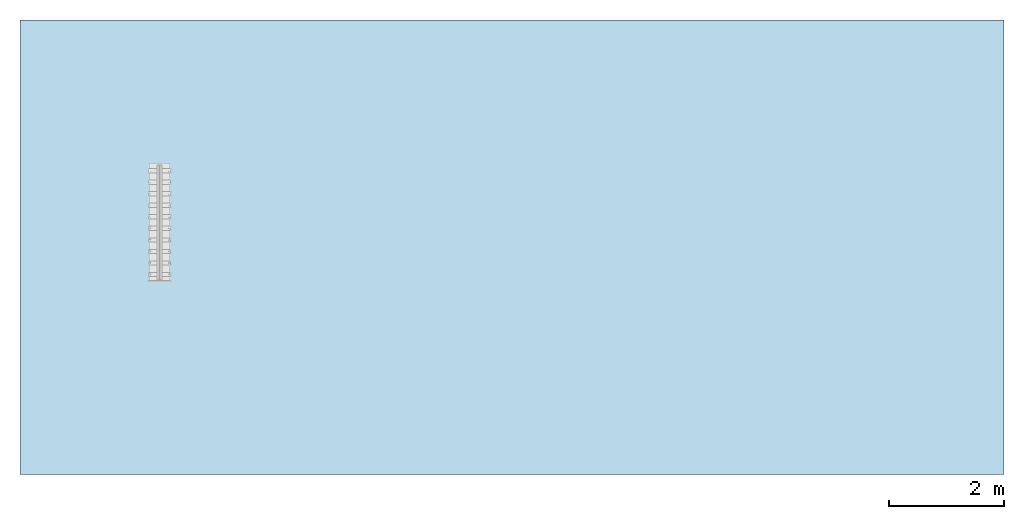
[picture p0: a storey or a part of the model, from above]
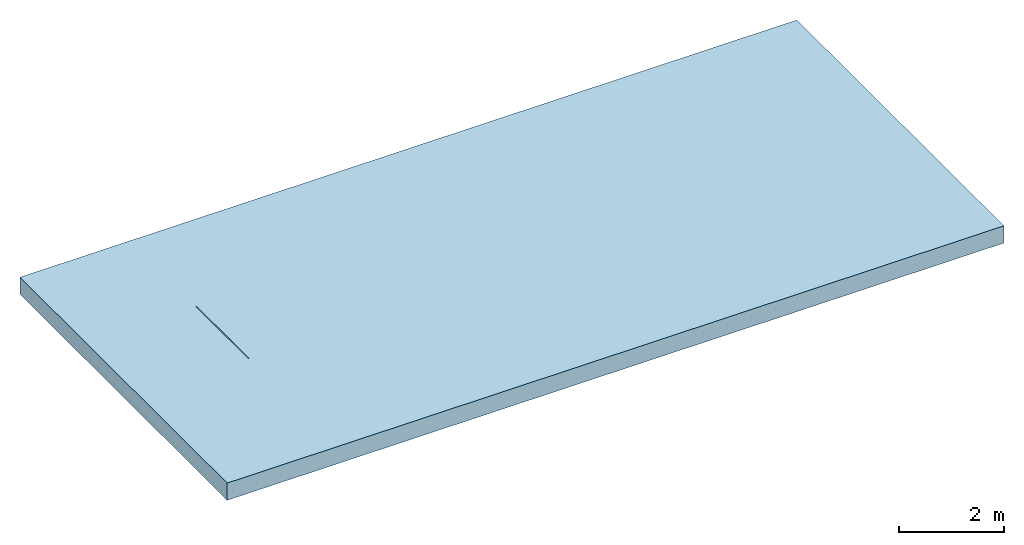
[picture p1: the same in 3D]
Properties of the parts of a building model (IFC2X3)

# File
Description: ViewDefinition [CoordinationView]
File name: 32814 - Q-Slot Edge - G.S.ifc
Time: 2013-07-12T11:23:24
Written by: Autodesk Revit 2013
Made in: 20120221_2030(x64)

# IfcProject, Project Number
LongName: Project Name; Phase: Project Status

# IfcSite, Default
RefLatitude: 42, 21, 30, 344238; RefLongitude: -71, -3, -35, -194702; RefElevation: 0 mm

# IfcBuilding
Pset_BuildingCommon - NumberOfStoreys: 1
Other - Project Address: ## Street City, State Zip; Project Name: Project Name; Client Name: Owner; Project Number: Project Number; Project Status: Project Status; Project Issue Date: Issue Date

# IfcBuildingStorey, Level 1
LongName: Level 1; Elevation: 0 mm
Constraints - Elevation Base: 0; Elevation: 0 mm
Graphics - Line Pattern: Center; Symbol at End 2 Default: yes; Symbol: M_Level Head - Circle: M_Level Head - Circle; Line Weight: 1; Symbol at End 1 Default: no; Color: 0
Identity Data - Structural: no; Building Story: yes; Name: Level 1
Dimensions - Computation Height: 0 mm

# IfcFlowTerminal: 32814 - Q-Slot Edge - G.S, Qmax 350:32814 - Q-Slot Edge - G.S:32814 - Q-Slot Edge - G.S:562865
In: Level 1
Identity Data - Mark: 40; OmniClass Number: 23.70.50.24; URL: www.aco.co.uk; OmniClass Title: Rainwater Removal; Product Page URL: http://www.aco.co.uk/product_detail.php?id=79; Address: ACO Business Park, Hitchin Road, Shefford, Bedfordshire, United Kingdom SG17 5TE; Maintenance Guidelines: http://www.aco.co.uk/download.php?id=220; e-mail Technical: technical@aco.co.uk; Fax: +44 (0)1462 815895; Assembly Code: D2040; Product Brochure: http://www.aco.co.uk/download.php?id=220; Product Code: 32814; Installation Guidelines: http://www.aco.co.uk/download.php?id=220; Telephone: +44 (0)1462 816666; Price: POA - contact ACO; Type Comments: ACO Qmax 350 channel assembly complete with ACO Q-Slot galvanised steel edge rail; Manufacturer: ACO Technologies plc - ACO Water Management Division; Model Description: High capacity slot drainage channel system; Model: ACO Qmax 350; Cost: 0; e-mail Sales: customersupport@aco.co.uk; Assembly Description: Rain Water Drainage
Constraints - Moves With Nearby Elements: no; Level: Level: Level 1
Construction - 42351_350 End Cap (Female end): no; 42351_350 End Cap (Male end): no; 32880_225-350 Step Connector: no; E1-QFlow-DuctileIron: no; E5-QSlot-GalvSteel: yes; E3-QFlow-GalvSteel: no; V_Coarse_E5: yes; E2-QGuard-DuctileIron: no; V_CoarseE1: no; E4-QGuard-GalvSteel: no
Phasing - Phase Created: New Construction
Materials and Finishes - Seal Colour: Black; Edge Rail Colour: Silver; Seal Material: Chloroprene; Channel Colour: Black; Edge Rail Finish: Galvanised; Channel Material: Medium Density Polyethylene; Edge Rail Material: Steel
Green Building Properties - Channel Recyclable: Fully recyclable; Seal Recyclable: Fully recyclable; Edge Rail Recycled Material Content: Between 40% - 90%; Edge Rail Recyclable: Fully recyclable; Channel Recycled Material Content: Variable %; Seal Recycled Material Content: 0%
Model Properties - Multi-Functional End Cap - Model Description: High capacity slot drainage channel system; Multi-Functional End Cap - Seal Recycled Material Content: 0%; 225-350 Step Connector - Dimensions: Ø435mm x 25mm (ØxL); 225-350 Step Connector - Recycled Material Content: 0%; Multi-Functional End Cap - Dimensions: Ø435mm x 260mm (ØxL); Multi-Functional End Cap - Seal Material: Chloroprene; Multi-Functional End Cap - Seal Recyclable: Fully recyclable; Multi-Functional End Cap - Channel Recycled Material Content: Variable %; Multi-Functional End Cap - Product Code: 42351; 225-350 Step Connector - Product Code: 32880; 225-350 Step Connector - Recyclable: Fully recyclable; 225-350 Step Connector- Colour: Black; Multi-Functional End Cap - Channel Recyclable: Fully recyclable; Multi-Functional End Cap - Weight: 2.6 kg; 225-350 Step Connector - Material: High Density Polyethylene; Multi-Functional End Cap - Seal Colour: Black; Multi-Functional End Cap - Channel Material: Medium Density Polyethylene; 225-350 Step Connector - Weight: 0.8 kg; 225-350 Step Connector - Model Description: High capacity slot drainage channel system; Multi-Functional End Cap - Channel Colour: Black
Other - Created by: www.aco.co.uk; Revision: 1
Data - Installation - Reinforcement Details: Refer to brochure; Product Weight: 29.1kg; Installation - Concrete Grade: Refer to brochure; Product Standard: BS EN 1433:2002 CE marked; Channel C.S.A: 96211mm²; Load Class: A 15 - F 900; Concrete Surround Volume - Load Class A 15 - E 600: 0.34 m³/m; Drainage Slot Width: 10mm; Invert Depth: 650mm; Drainage Slot Intake Area: 10000mm²/m; Concrete Surround Volume - Load Class F 900: 0.45 m³/m; Product Dimensions: 2000mm x 415mm x 700mm (LxWxH); ACO Hydraulic Design Software: http://www.acodesign.co.uk; Hydraulic Performance: http://www.aco.co.uk/download.php?id=220
General - TagNumber: 0; SerialNumber: 0
Dimensions - Depth Overall: 700 mm; Floor Opening Width: 18 mm; Length: 2000 mm; BoreCentre: 470 mm; Width Overall: 415 mm

# IfcOpeningElement: Opening
In: Level 1
Structural - Structural: no; Enable Analytical Model: no
Constraints - Level: Level: Level 1; Related to Mass: no; Room Bounding: yes; Height Offset From Level: 0 mm
Phasing - Phase Created: New Construction
Dimensions - Volume: 53727820000 mm3; Area: 135054000 mm2; Perimeter: 50000 mm; Thickness: 400 mm
Graphics - Coarse Scale Fill Color: 0
Materials and Finishes - Structural Material: Plant
Construction - Default Thickness: 400 mm; Function: 0
Analytical Properties - Absorptance: 0.1; Roughness: 1

# IfcSlab: Floor:Generic Floor - 400mm, Floor:Generic Floor - 400mm:193825
In: Level 1
PredefinedType: FLOOR; Material: Plant 400 mm
Structural - Structural: no; Enable Analytical Model: no
Constraints - Level: Level: Level 1; Related to Mass: no; Room Bounding: yes; Height Offset From Level: 0 mm
Phasing - Phase Created: New Construction
Dimensions - Volume: 53727820000 mm3; Area: 135054000 mm2; Perimeter: 50000 mm; Thickness: 400 mm
Pset_SlabCommon - Reference: Generic Floor - 400mm; IsExternal: no; LoadBearing: yes
Graphics - Coarse Scale Fill Color: 0
Materials and Finishes - Structural Material: Plant
Construction - Default Thickness: 400 mm; Function: 0
Analytical Properties - Absorptance: 0.1; Roughness: 1
